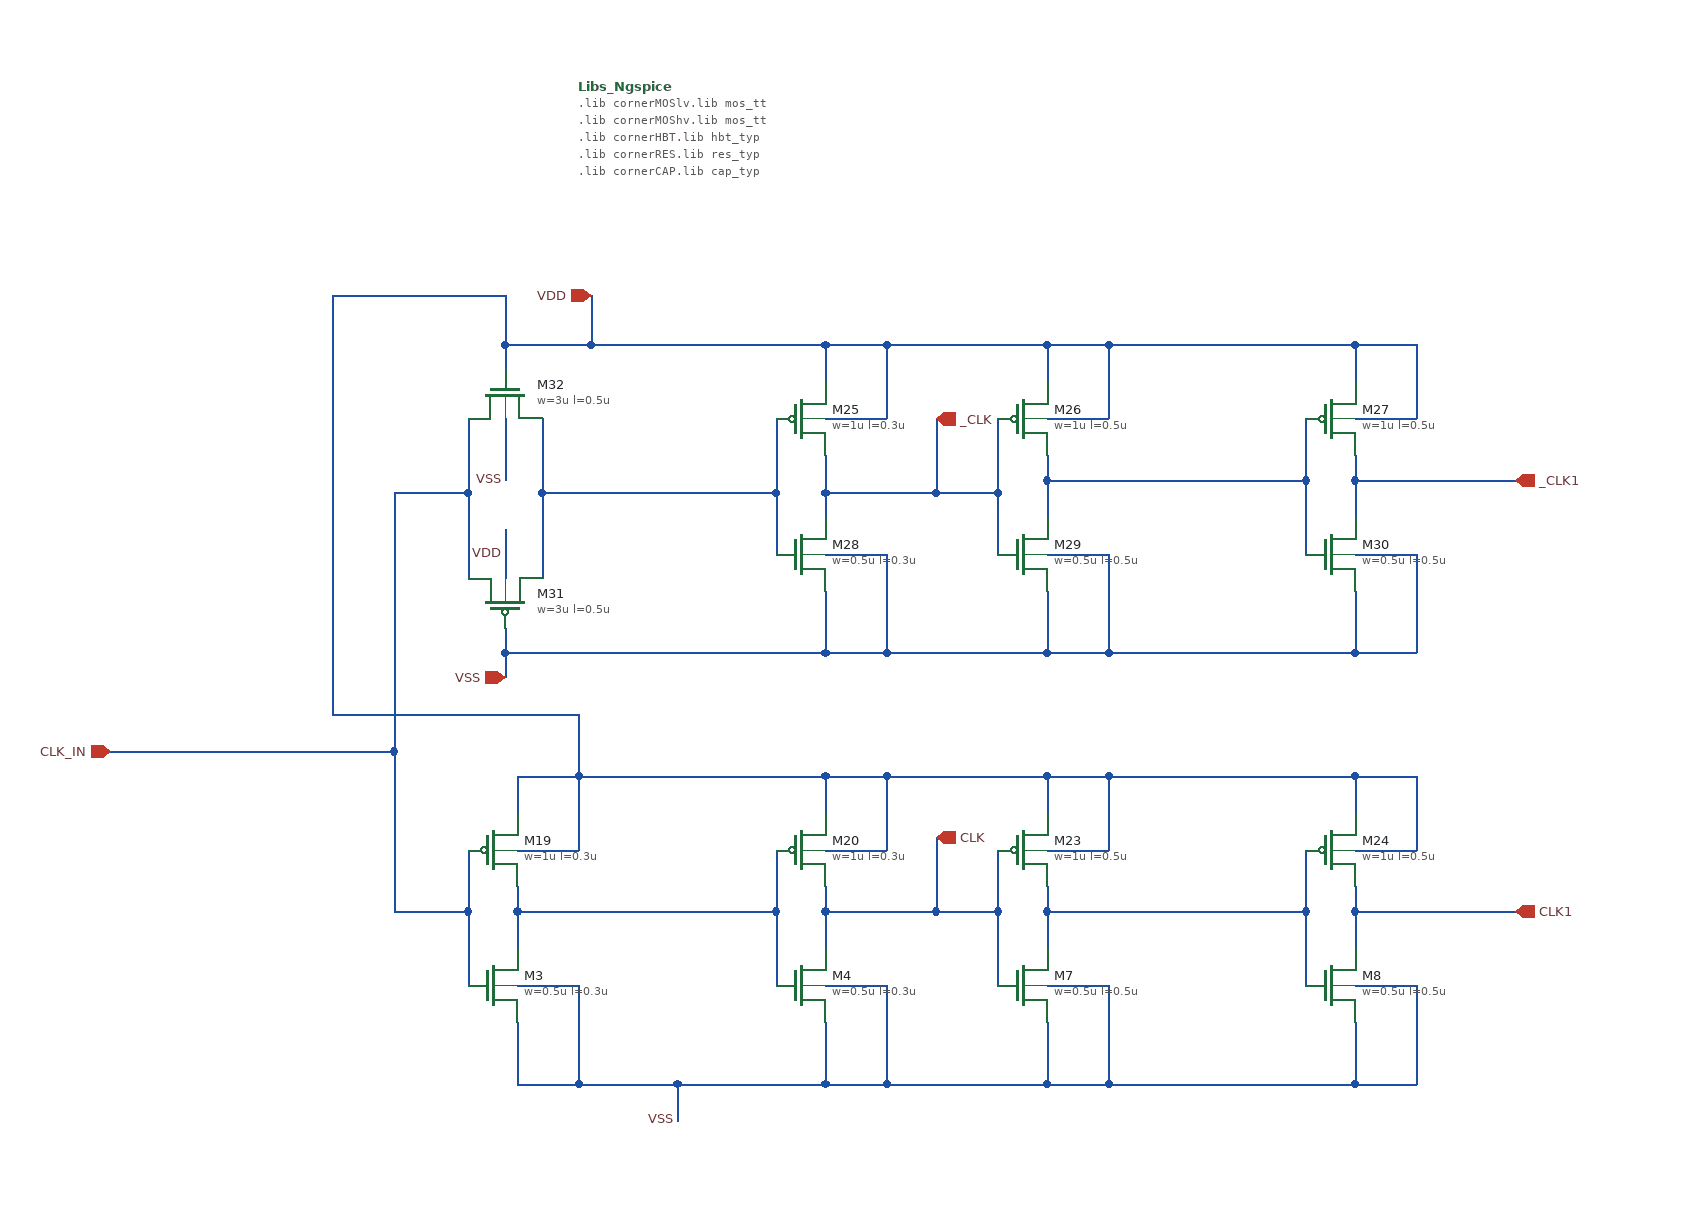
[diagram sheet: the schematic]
v {xschem version=3.4.6 file_version=1.2}
G {}
K {}
V {}
S {}
E {}
N 380 190 380 260 {lab=CLK_IN}
N 440 190 440 260 {lab=#net1}
N 410 130 410 180 {lab=VSS}
N 410 220 410 260 {lab=VDD}
N 410 320 410 340 {lab=VSS}
N 410 70 410 90 {lab=VDD}
N 320 190 320 400 {lab=CLK_IN}
N 320 190 380 190 {lab=CLK_IN}
N 630 190 630 240 {lab=#net1}
N 440 190 630 190 {lab=#net1}
N 670 190 670 220 {lab=_CLK}
N 760 190 810 190 {lab=_CLK}
N 480 70 670 70 {lab=VDD}
N 670 70 670 100 {lab=VDD}
N 410 320 670 320 {lab=VSS}
N 670 270 670 320 {lab=VSS}
N 670 130 720 130 {lab=VDD}
N 720 70 720 130 {lab=VDD}
N 670 70 720 70 {lab=VDD}
N 670 240 720 240 {lab=VSS}
N 720 240 720 320 {lab=VSS}
N 670 320 720 320 {lab=VSS}
N 380 530 380 590 {lab=CLK_IN}
N 420 530 420 570 {lab=#net2}
N 420 420 420 450 {lab=VDD}
N 420 620 420 670 {lab=VSS}
N 420 480 470 480 {lab=VDD}
N 470 420 470 480 {lab=VDD}
N 420 420 470 420 {lab=VDD}
N 420 590 470 590 {lab=VSS}
N 470 590 470 670 {lab=VSS}
N 420 670 470 670 {lab=VSS}
N 320 400 320 530 {lab=CLK_IN}
N 320 530 380 530 {lab=CLK_IN}
N 630 530 630 590 {lab=#net2}
N 670 530 670 570 {lab=CLK}
N 670 420 670 450 {lab=VDD}
N 670 620 670 670 {lab=VSS}
N 670 480 720 480 {lab=VDD}
N 720 420 720 480 {lab=VDD}
N 670 420 720 420 {lab=VDD}
N 670 590 720 590 {lab=VSS}
N 720 590 720 670 {lab=VSS}
N 670 670 720 670 {lab=VSS}
N 420 530 630 530 {lab=#net2}
N 760 530 810 530 {lab=CLK}
N 470 420 670 420 {lab=VDD}
N 550 670 670 670 {lab=VSS}
N 470 370 470 420 {lab=VDD}
N 270 370 470 370 {lab=VDD}
N 270 30 270 370 {lab=VDD}
N 270 30 410 30 {lab=VDD}
N 550 670 550 700 {lab=VSS}
N 810 530 810 590 {lab=CLK}
N 850 530 850 570 {lab=#net3}
N 850 420 850 450 {lab=VDD}
N 850 620 850 670 {lab=VSS}
N 850 480 900 480 {lab=VDD}
N 900 420 900 480 {lab=VDD}
N 850 420 900 420 {lab=VDD}
N 850 590 900 590 {lab=VSS}
N 900 590 900 670 {lab=VSS}
N 850 670 900 670 {lab=VSS}
N 1060 530 1060 590 {lab=#net3}
N 1100 530 1100 570 {lab=CLK1}
N 1100 420 1100 450 {lab=VDD}
N 1100 620 1100 670 {lab=VSS}
N 1100 480 1150 480 {lab=VDD}
N 1150 420 1150 480 {lab=VDD}
N 1100 420 1150 420 {lab=VDD}
N 1100 590 1150 590 {lab=VSS}
N 1150 590 1150 670 {lab=VSS}
N 1100 670 1150 670 {lab=VSS}
N 850 530 1060 530 {lab=#net3}
N 900 420 1100 420 {lab=VDD}
N 900 670 1100 670 {lab=VSS}
N 1100 530 1230 530 {lab=CLK1}
N 810 190 810 240 {lab=_CLK}
N 850 180 850 220 {lab=#net4}
N 850 70 850 100 {lab=VDD}
N 850 270 850 320 {lab=VSS}
N 850 130 900 130 {lab=VDD}
N 900 70 900 130 {lab=VDD}
N 850 70 900 70 {lab=VDD}
N 850 240 900 240 {lab=VSS}
N 900 240 900 320 {lab=VSS}
N 1060 180 1060 240 {lab=#net4}
N 1100 180 1100 220 {lab=_CLK1}
N 1100 70 1100 100 {lab=VDD}
N 1100 270 1100 320 {lab=VSS}
N 1100 130 1150 130 {lab=VDD}
N 1150 70 1150 130 {lab=VDD}
N 1100 70 1150 70 {lab=VDD}
N 1100 240 1150 240 {lab=VSS}
N 1150 240 1150 320 {lab=VSS}
N 1100 320 1150 320 {lab=VSS}
N 850 180 1060 180 {lab=#net4}
N 900 70 1100 70 {lab=VDD}
N 900 320 1100 320 {lab=VSS}
N 1100 180 1230 180 {lab=_CLK1}
N 720 70 850 70 {lab=VDD}
N 850 320 900 320 {lab=VSS}
N 720 420 850 420 {lab=VDD}
N 720 670 850 670 {lab=VSS}
N 90 400 320 400 {lab=CLK_IN}
N 380 130 380 190 {lab=CLK_IN}
N 440 130 440 190 {lab=#net1}
N 630 130 630 190 {lab=#net1}
N 670 160 670 190 {lab=_CLK}
N 810 130 810 190 {lab=_CLK}
N 410 30 410 70 {lab=VDD}
N 410 300 410 320 {lab=VSS}
N 380 480 380 530 {lab=CLK_IN}
N 420 510 420 530 {lab=#net2}
N 630 480 630 530 {lab=#net2}
N 670 510 670 530 {lab=CLK}
N 810 480 810 530 {lab=CLK}
N 470 670 550 670 {lab=VSS}
N 850 510 850 530 {lab=#net3}
N 1060 480 1060 530 {lab=#net3}
N 1100 510 1100 530 {lab=CLK1}
N 720 320 850 320 {lab=VSS}
N 850 160 850 180 {lab=#net4}
N 1060 130 1060 180 {lab=#net4}
N 1100 160 1100 180 {lab=_CLK1}
N 480 30 480 70 {lab=VDD}
N 410 70 480 70 {lab=VDD}
N 760 470 760 530 {lab=CLK}
N 670 530 760 530 {lab=CLK}
N 760 130 760 190 {lab=_CLK}
N 670 190 760 190 {lab=_CLK}
C {simulator_commands_shown.sym} 470 -140 0 0 {
name=Libs_Ngspice
simulator=ngspice
only_toplevel=false
value="
.lib cornerMOSlv.lib mos_tt
.lib cornerMOShv.lib mos_tt
.lib cornerHBT.lib hbt_typ
.lib cornerRES.lib res_typ
.lib cornerCAP.lib cap_typ
"
      }
C {lab_wire.sym} 410 240 0 0 {name=p7 sig_type=std_logic lab=VDD}
C {noconn.sym} 810 190 2 0 {name=l1}
C {noconn.sym} 810 530 2 0 {name=l6}
C {noconn.sym} 810 180 2 0 {name=l11}
C {sg13g2_pr/sg13_lv_nmos.sym} 400 590 0 0 {name=M3
l=0.3u
w=0.5u
ng=1
m=1
model=sg13_lv_nmos
spiceprefix=X
}
C {sg13g2_pr/sg13_lv_nmos.sym} 650 590 0 0 {name=M4
l=0.3u
w=0.5u
ng=1
m=1
model=sg13_lv_nmos
spiceprefix=X
}
C {sg13g2_pr/sg13_lv_nmos.sym} 830 590 0 0 {name=M7
l=0.5u
w=0.5u
ng=1
m=1
model=sg13_lv_nmos
spiceprefix=X
}
C {sg13g2_pr/sg13_lv_nmos.sym} 1080 590 0 0 {name=M8
l=0.5u
w=0.5u
ng=1
m=1
model=sg13_lv_nmos
spiceprefix=X
}
C {sg13g2_pr/sg13_lv_pmos.sym} 400 480 0 0 {name=M19
l=0.3u
w=1u
ng=1
m=1
model=sg13_lv_pmos
spiceprefix=X
}
C {sg13g2_pr/sg13_lv_pmos.sym} 650 480 0 0 {name=M20
l=0.3u
w=1u
ng=1
m=1
model=sg13_lv_pmos
spiceprefix=X
}
C {sg13g2_pr/sg13_lv_pmos.sym} 830 480 0 0 {name=M23
l=0.5u
w=1u
ng=2
m=1
model=sg13_lv_pmos
spiceprefix=X
}
C {sg13g2_pr/sg13_lv_pmos.sym} 1080 480 0 0 {name=M24
l=0.5u
w=1u
ng=2
m=1
model=sg13_lv_pmos
spiceprefix=X
}
C {sg13g2_pr/sg13_lv_pmos.sym} 650 130 0 0 {name=M25
l=0.3u
w=1u
ng=1
m=1
model=sg13_lv_pmos
spiceprefix=X
}
C {sg13g2_pr/sg13_lv_pmos.sym} 830 130 0 0 {name=M26
l=0.5u
w=1u
ng=2
m=1
model=sg13_lv_pmos
spiceprefix=X
}
C {sg13g2_pr/sg13_lv_pmos.sym} 1080 130 0 0 {name=M27
l=0.5u
w=1u
ng=2
m=1
model=sg13_lv_pmos
spiceprefix=X
}
C {sg13g2_pr/sg13_lv_nmos.sym} 650 240 0 0 {name=M28
l=0.3u
w=0.5u
ng=1
m=1
model=sg13_lv_nmos
spiceprefix=X
}
C {sg13g2_pr/sg13_lv_nmos.sym} 830 240 0 0 {name=M29
l=0.5u
w=0.5u
ng=1
m=1
model=sg13_lv_nmos
spiceprefix=X
}
C {sg13g2_pr/sg13_lv_nmos.sym} 1080 240 0 0 {name=M30
l=0.5u
w=0.5u
ng=1
m=1
model=sg13_lv_nmos
spiceprefix=X
}
C {sg13g2_pr/sg13_lv_pmos.sym} 410 280 3 0 {name=M31
l=0.5u
w=3u
ng=5
m=1
model=sg13_lv_pmos
spiceprefix=X
}
C {sg13g2_pr/sg13_lv_nmos.sym} 410 110 1 0 {name=M32
l=0.5u
w=3u
ng=5
m=1
model=sg13_lv_nmos
spiceprefix=X
}
C {ipin.sym} 90 400 0 0 {name=p9 sig_type=std_logic lab=CLK_IN}
C {ipin.sym} 480 30 0 0 {name=p12 lab=VDD}
C {opin.sym} 1230 180 0 0 {name=p11 sig_type=std_logic lab=_CLK1}
C {opin.sym} 1230 530 0 0 {name=p10 sig_type=std_logic lab=CLK1}
C {opin.sym} 760 470 3 0 {name=p13 sig_type=std_logic lab=CLK}
C {opin.sym} 760 130 3 0 {name=p8 sig_type=std_logic lab=_CLK}
C {ipin.sym} 410 340 0 0 {name=p14 lab=VSS}
C {lab_wire.sym} 410 180 0 0 {name=p15 sig_type=std_logic lab=VSS}
C {lab_wire.sym} 550 700 0 0 {name=p16 sig_type=std_logic lab=VSS}
